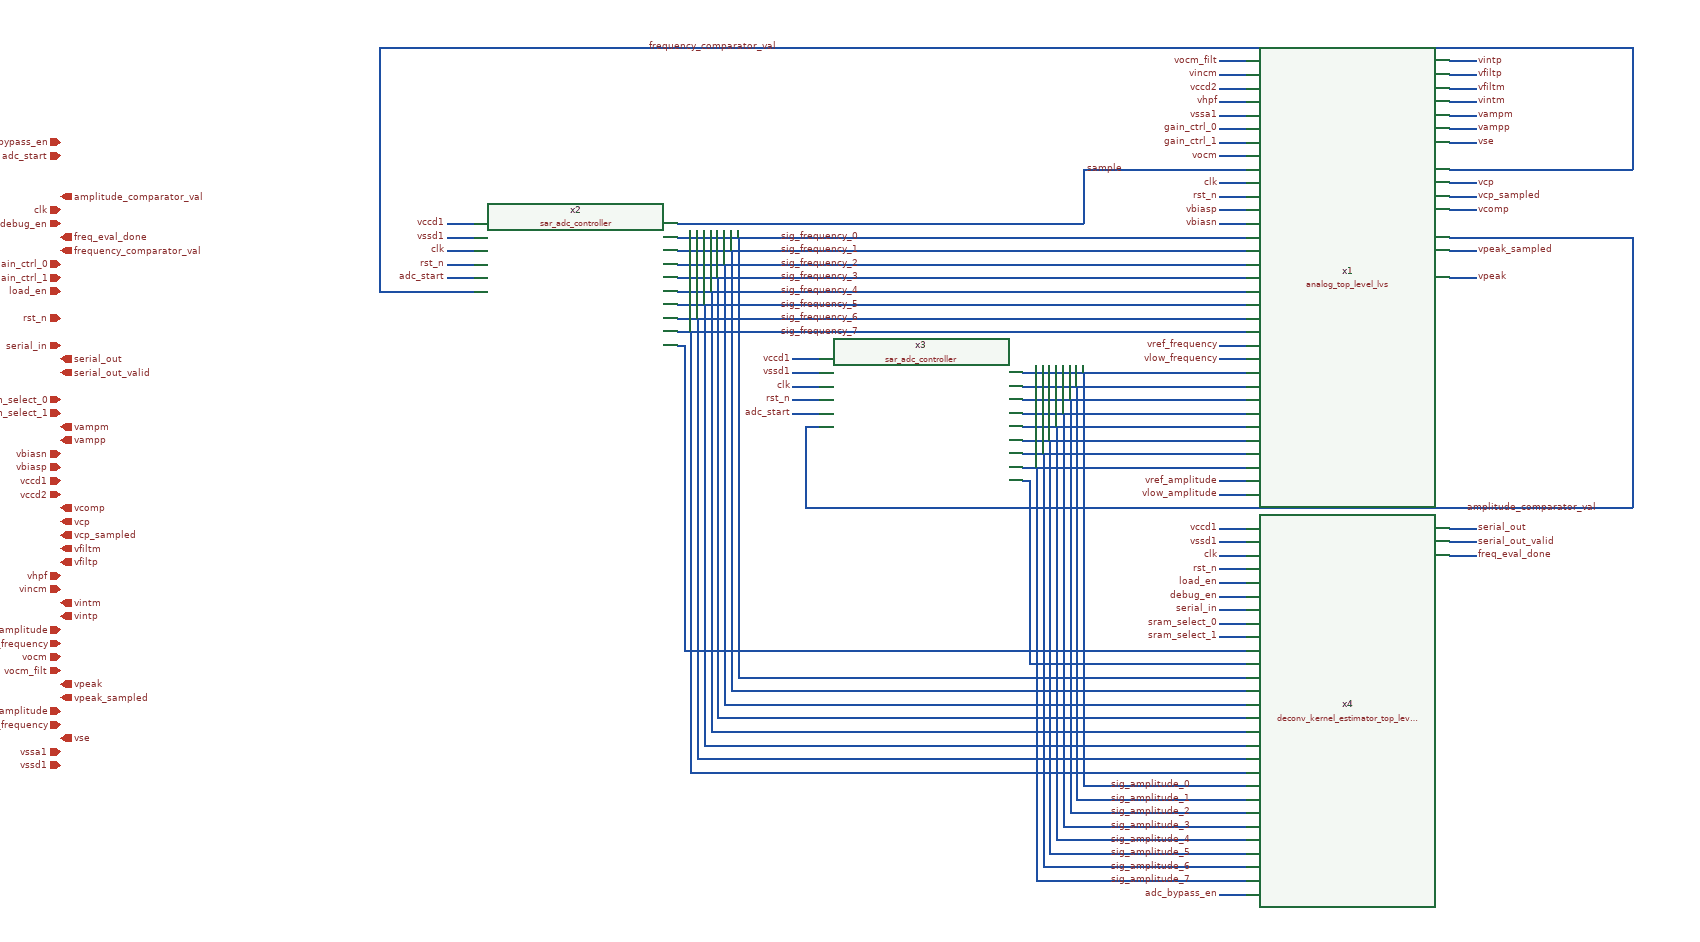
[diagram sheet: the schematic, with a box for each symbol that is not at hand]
v {xschem version=2.9.9 file_version=1.2 }
G {}
K {}
V {}
S {}
E {}
N 1400 -700 1440 -700 { lab=vlow_amplitude}
N 1400 -720 1440 -720 { lab=vref_amplitude}
N 1400 -900 1440 -900 { lab=vlow_frequency}
N 1400 -920 1440 -920 { lab=vref_frequency}
N 1400 -1100 1440 -1100 { lab=vbiasn}
N 1400 -1120 1440 -1120 { lab=vbiasp}
N 1400 -1200 1440 -1200 { lab=vocm}
N 1400 -1280 1440 -1280 { lab=vhpf}
N 1400 -1320 1440 -1320 { lab=vincm}
N 1400 -1340 1440 -1340 { lab=vocm_filt}
N 1740 -1340 1780 -1340 { lab=vfiltp}
N 1740 -1320 1780 -1320 { lab=vfiltp}
N 1740 -1300 1780 -1300 { lab=vfiltm}
N 1740 -1280 1780 -1280 { lab=vintm}
N 1740 -1260 1780 -1260 { lab=vampm}
N 1740 -1240 1780 -1240 { lab=vampp}
N 1740 -1220 1780 -1220 { lab=vse}
N 1740 -1160 1780 -1160 { lab=vcp}
N 1740 -1140 1780 -1140 { lab=vcp_sampled}
N 1740 -1020 1780 -1020 { lab=vpeak}
N 1740 -1060 1780 -1060 { lab=vpeak_sampled}
N 1740 -1120 1780 -1120 { lab=vcomp}
N 1400 -1240 1440 -1240 { lab=gain_ctrl_0}
N 1400 -1220 1440 -1220 { lab=gain_ctrl_1}
N 1400 -1180 1440 -1180 { lab=sample}
N 1400 -1160 1440 -1160 { lab=clk}
N 1400 -1300 1440 -1300 { lab=vccd2}
N 1400 -1260 1440 -1260 { lab=vssa1}
N 1200 -1180 1400 -1180 { lab=sample}
N 600 -1080 1440 -1080 { lab=sig_frequency_0}
N 1130 -740 1130 -510 { lab=sig_amplitude_7}
N 1140 -760 1140 -520 { lab=sig_amplitude_6}
N 1150 -780 1150 -530 { lab=sig_amplitude_5}
N 1160 -800 1160 -540 { lab=sig_amplitude_4}
N 1170 -820 1170 -550 { lab=sig_amplitude_3}
N 1180 -840 1180 -560 { lab=sig_amplitude_2}
N 1190 -860 1190 -570 { lab=sig_amplitude_1}
N 1200 -880 1200 -580 { lab=sig_amplitude_0}
N 1200 -270 1440 -270 { lab=sig_amplitude_0}
N 1190 -250 1440 -250 { lab=sig_amplitude_1}
N 1180 -230 1440 -230 { lab=sig_amplitude_2}
N 1170 -210 1440 -210 { lab=sig_amplitude_3}
N 1160 -190 1440 -190 { lab=sig_amplitude_4}
N 1150 -170 1440 -170 { lab=sig_amplitude_5}
N 1140 -150 1440 -150 { lab=sig_amplitude_6}
N 1130 -130 1440 -130 { lab=sig_amplitude_7}
N 1110 -880 1440 -880 { lab=sig_amplitude_0}
N 1110 -860 1440 -860 { lab=sig_amplitude_1}
N 1110 -840 1440 -840 { lab=sig_amplitude_2}
N 1110 -820 1440 -820 { lab=sig_amplitude_3}
N 1110 -800 1440 -800 { lab=sig_amplitude_4}
N 1110 -780 1440 -780 { lab=sig_amplitude_5}
N 1110 -760 1440 -760 { lab=sig_amplitude_6}
N 1110 -740 1440 -740 { lab=sig_amplitude_7}
N 1200 -580 1200 -270 { lab=sig_amplitude_0}
N 1190 -570 1190 -250 { lab=sig_amplitude_1}
N 1180 -560 1180 -230 { lab=sig_amplitude_2}
N 1170 -550 1170 -210 { lab=sig_amplitude_3}
N 1160 -540 1160 -190 { lab=sig_amplitude_4}
N 1150 -530 1150 -170 { lab=sig_amplitude_5}
N 1140 -520 1140 -150 { lab=sig_amplitude_6}
N 1130 -510 1130 -130 { lab=sig_amplitude_7}
N 620 -940 620 -710 { lab=sig_frequency_7}
N 630 -960 630 -720 { lab=sig_frequency_6}
N 640 -980 640 -730 { lab=sig_frequency_5}
N 650 -1000 650 -740 { lab=sig_frequency_4}
N 660 -1020 660 -750 { lab=sig_frequency_3}
N 670 -1040 670 -760 { lab=sig_frequency_2}
N 680 -1060 680 -770 { lab=sig_frequency_1}
N 690 -1080 690 -780 { lab=sig_frequency_0}
N 620 -290 1440 -290 { lab=sig_frequency_7}
N 620 -710 620 -290 { lab=sig_frequency_7}
N 630 -720 630 -310 { lab=sig_frequency_6}
N 630 -310 1440 -310 { lab=sig_frequency_6}
N 640 -330 1440 -330 { lab=sig_frequency_5}
N 640 -730 640 -330 { lab=sig_frequency_5}
N 650 -740 650 -350 { lab=sig_frequency_4}
N 650 -350 1440 -350 { lab=sig_frequency_4}
N 660 -370 1440 -370 { lab=sig_frequency_3}
N 660 -750 660 -370 { lab=sig_frequency_3}
N 670 -760 670 -390 { lab=sig_frequency_2}
N 670 -390 1440 -390 { lab=sig_frequency_2}
N 680 -410 1440 -410 { lab=sig_frequency_1}
N 680 -770 680 -410 { lab=sig_frequency_1}
N 690 -780 690 -430 { lab=sig_frequency_0}
N 690 -430 1440 -430 { lab=sig_frequency_0}
N 600 -1060 1440 -1060 { lab=sig_frequency_1}
N 600 -1040 1440 -1040 { lab=sig_frequency_2}
N 600 -1020 1440 -1020 { lab=sig_frequency_3}
N 600 -1000 1440 -1000 { lab=sig_frequency_4}
N 600 -980 1440 -980 { lab=sig_frequency_5}
N 600 -960 1440 -960 { lab=sig_frequency_6}
N 600 -940 1440 -940 { lab=sig_frequency_7}
N 600 -1100 1200 -1100 { lab=sample}
N 770 -900 810 -900 { lab=vccd1}
N 1400 -650 1440 -650 { lab=vccd1}
N 260 -1100 300 -1100 { lab=vccd1}
N 260 -1080 300 -1080 { lab=vssd1}
N 770 -880 810 -880 { lab=vssd1}
N 1400 -630 1440 -630 { lab=vssd1}
N 1110 -720 1120 -720 { lab=#net1}
N 1120 -720 1120 -450 { lab=#net1}
N 1120 -450 1440 -450 { lab=#net1}
N 600 -920 610 -920 { lab=#net2}
N 610 -470 1440 -470 { lab=#net2}
N 610 -920 610 -470 { lab=#net2}
N 1400 -510 1440 -510 { lab=sram_select_0}
N 1400 -490 1440 -490 { lab=sram_select_1}
N 1400 -610 1440 -610 { lab=clk}
N 1400 -590 1440 -590 { lab=rst_n}
N 260 -1060 300 -1060 { lab=clk}
N 260 -1040 300 -1040 { lab=rst_n}
N 770 -860 810 -860 { lab=clk}
N 770 -840 810 -840 { lab=rst_n}
N 260 -1020 300 -1020 { lab=adc_start}
N 770 -820 810 -820 { lab=adc_start}
N 160 -1360 2010 -1360 { lab=frequency_comparator_val}
N 160 -1360 160 -1000 { lab=frequency_comparator_val}
N 160 -1000 300 -1000 { lab=frequency_comparator_val}
N 2010 -1060 2010 -680 { lab=amplitude_comparator_val}
N 790 -680 2010 -680 { lab=amplitude_comparator_val}
N 790 -800 790 -680 { lab=amplitude_comparator_val}
N 790 -800 810 -800 { lab=amplitude_comparator_val}
N 1400 -570 1440 -570 { lab=load_en}
N 1400 -550 1440 -550 { lab=debug_en}
N 1400 -530 1440 -530 { lab=serial_in}
N 1740 -650 1780 -650 { lab=serial_out}
N 1740 -630 1780 -630 { lab=serial_out_valid}
N 1740 -610 1780 -610 { lab=freq_eval_done}
N 1400 -110 1440 -110 { lab=adc_bypass_en}
N 1200 -1180 1200 -1160 { lab=sample}
N 1400 -1140 1440 -1140 { lab=rst_n}
N 1740 -1180 2010 -1180 { lab=frequency_comparator_val}
N 2010 -1360 2010 -1180 { lab=frequency_comparator_val}
N 1740 -1080 2010 -1080 { lab=amplitude_comparator_val}
N 2010 -1080 2010 -1060 { lab=amplitude_comparator_val}
N 1200 -1160 1200 -1100 { lab=sample}
C {/home/users/nhpoole/ee272b/ee272b_mixed_signal_mmwave_accelerator/designs/analog_top_level_lvs.sym} 1590 -1020 0 0 {name=x1}
C {devices/lab_pin.sym} 1400 -700 0 0 {name=l13 sig_type=std_logic lab=vlow_amplitude}
C {devices/lab_pin.sym} 1400 -720 0 0 {name=l14 sig_type=std_logic lab=vref_amplitude}
C {devices/lab_pin.sym} 1400 -900 0 0 {name=l15 sig_type=std_logic lab=vlow_frequency}
C {devices/lab_pin.sym} 1400 -920 0 0 {name=l16 sig_type=std_logic lab=vref_frequency}
C {devices/lab_pin.sym} 1400 -1100 0 0 {name=l17 sig_type=std_logic lab=vbiasn}
C {devices/lab_pin.sym} 1400 -1120 0 0 {name=l18 sig_type=std_logic lab=vbiasp}
C {devices/lab_pin.sym} 1400 -1200 0 0 {name=l19 sig_type=std_logic lab=vocm}
C {devices/lab_pin.sym} 1400 -1280 0 0 {name=l20 sig_type=std_logic lab=vhpf}
C {devices/lab_pin.sym} 1400 -1320 0 0 {name=l21 sig_type=std_logic lab=vincm}
C {devices/lab_pin.sym} 1400 -1340 0 0 {name=l22 sig_type=std_logic lab=vocm_filt}
C {devices/lab_pin.sym} 1780 -1340 0 1 {name=l23 sig_type=std_logic lab=vintp}
C {devices/lab_pin.sym} 1780 -1320 0 1 {name=l24 sig_type=std_logic lab=vfiltp}
C {devices/lab_pin.sym} 1780 -1300 0 1 {name=l25 sig_type=std_logic lab=vfiltm}
C {devices/lab_pin.sym} 1780 -1280 0 1 {name=l26 sig_type=std_logic lab=vintm}
C {devices/lab_pin.sym} 1780 -1260 0 1 {name=l27 sig_type=std_logic lab=vampm}
C {devices/lab_pin.sym} 1780 -1240 0 1 {name=l28 sig_type=std_logic lab=vampp}
C {devices/lab_pin.sym} 1780 -1220 0 1 {name=l31 sig_type=std_logic lab=vse}
C {devices/lab_pin.sym} 1780 -1160 0 1 {name=l32 sig_type=std_logic lab=vcp}
C {devices/lab_pin.sym} 1780 -1140 0 1 {name=l33 sig_type=std_logic lab=vcp_sampled}
C {devices/lab_pin.sym} 1780 -1020 0 1 {name=l34 sig_type=std_logic lab=vpeak}
C {devices/lab_pin.sym} 1780 -1060 0 1 {name=l35 sig_type=std_logic lab=vpeak_sampled}
C {devices/lab_pin.sym} 1780 -1120 0 1 {name=l36 sig_type=std_logic lab=vcomp}
C {devices/lab_pin.sym} 1400 -1240 0 0 {name=l40 sig_type=std_logic lab=gain_ctrl_0}
C {devices/lab_pin.sym} 1400 -1220 0 0 {name=l41 sig_type=std_logic lab=gain_ctrl_1}
C {devices/lab_pin.sym} 1400 -1160 0 0 {name=l43 sig_type=std_logic lab=clk}
C {devices/lab_pin.sym} 1400 -1300 0 0 {name=l7 sig_type=std_logic lab=vccd2}
C {devices/lab_pin.sym} 1400 -1260 0 0 {name=l8 sig_type=std_logic lab=vssa1}
C {/home/users/nhpoole/ee272b/ee272b_mixed_signal_mmwave_accelerator/designs/sar_adc_controller.sym} 450 -1010 0 0 {name=x2}
C {/home/users/nhpoole/ee272b/ee272b_mixed_signal_mmwave_accelerator/designs/sar_adc_controller.sym} 960 -810 0 0 {name=x3}
C {/home/users/nhpoole/ee272b/ee272b_mixed_signal_mmwave_accelerator/designs/deconv_kernel_estimator_top_level.sym} 1590 -380 0 0 {name=x4}
C {devices/lab_wire.sym} 870 -1080 0 0 {name=l1 sig_type=std_logic lab=sig_frequency_0}
C {devices/lab_wire.sym} 870 -1060 0 0 {name=l2 sig_type=std_logic lab=sig_frequency_1}
C {devices/lab_wire.sym} 870 -1040 0 0 {name=l3 sig_type=std_logic lab=sig_frequency_2}
C {devices/lab_wire.sym} 870 -1020 0 0 {name=l4 sig_type=std_logic lab=sig_frequency_3}
C {devices/lab_wire.sym} 870 -1000 0 0 {name=l5 sig_type=std_logic lab=sig_frequency_4}
C {devices/lab_wire.sym} 870 -980 0 0 {name=l6 sig_type=std_logic lab=sig_frequency_5}
C {devices/lab_wire.sym} 870 -960 0 0 {name=l9 sig_type=std_logic lab=sig_frequency_6}
C {devices/lab_wire.sym} 870 -940 0 0 {name=l10 sig_type=std_logic lab=sig_frequency_7}
C {devices/lab_wire.sym} 1260 -1180 0 0 {name=l42 sig_type=std_logic lab=sample}
C {devices/lab_wire.sym} 1360 -270 0 0 {name=l11 sig_type=std_logic lab=sig_amplitude_0}
C {devices/lab_wire.sym} 1360 -250 0 0 {name=l12 sig_type=std_logic lab=sig_amplitude_1}
C {devices/lab_wire.sym} 1360 -230 0 0 {name=l44 sig_type=std_logic lab=sig_amplitude_2}
C {devices/lab_wire.sym} 1360 -210 0 0 {name=l45 sig_type=std_logic lab=sig_amplitude_3}
C {devices/lab_wire.sym} 1360 -190 0 0 {name=l46 sig_type=std_logic lab=sig_amplitude_4}
C {devices/lab_wire.sym} 1360 -170 0 0 {name=l47 sig_type=std_logic lab=sig_amplitude_5}
C {devices/lab_wire.sym} 1360 -150 0 0 {name=l48 sig_type=std_logic lab=sig_amplitude_6}
C {devices/lab_wire.sym} 1360 -130 0 0 {name=l49 sig_type=std_logic lab=sig_amplitude_7}
C {devices/noconn.sym} 1110 -900 0 1 {name=l50}
C {devices/lab_pin.sym} 770 -900 0 0 {name=l51 sig_type=std_logic lab=vccd1}
C {devices/lab_pin.sym} 1400 -650 0 0 {name=l52 sig_type=std_logic lab=vccd1}
C {devices/lab_pin.sym} 260 -1100 0 0 {name=l53 sig_type=std_logic lab=vccd1}
C {devices/lab_pin.sym} 260 -1080 0 0 {name=l54 sig_type=std_logic lab=vssd1}
C {devices/lab_pin.sym} 770 -880 0 0 {name=l55 sig_type=std_logic lab=vssd1}
C {devices/lab_pin.sym} 1400 -630 0 0 {name=l56 sig_type=std_logic lab=vssd1}
C {devices/lab_pin.sym} 1400 -510 0 0 {name=l57 sig_type=std_logic lab=sram_select_0}
C {devices/lab_pin.sym} 1400 -490 0 0 {name=l58 sig_type=std_logic lab=sram_select_1}
C {devices/lab_pin.sym} 1400 -610 0 0 {name=l59 sig_type=std_logic lab=clk}
C {devices/lab_pin.sym} 1400 -590 0 0 {name=l60 sig_type=std_logic lab=rst_n}
C {devices/lab_pin.sym} 260 -1060 0 0 {name=l61 sig_type=std_logic lab=clk}
C {devices/lab_pin.sym} 260 -1040 0 0 {name=l62 sig_type=std_logic lab=rst_n}
C {devices/lab_pin.sym} 770 -860 0 0 {name=l63 sig_type=std_logic lab=clk}
C {devices/lab_pin.sym} 770 -840 0 0 {name=l64 sig_type=std_logic lab=rst_n}
C {devices/lab_pin.sym} 260 -1020 0 0 {name=l65 sig_type=std_logic lab=adc_start}
C {devices/lab_pin.sym} 770 -820 0 0 {name=l66 sig_type=std_logic lab=adc_start}
C {devices/lab_wire.sym} 750 -1360 0 0 {name=l37 sig_type=std_logic lab=frequency_comparator_val}
C {devices/lab_wire.sym} 1960 -680 0 0 {name=l38 sig_type=std_logic lab=amplitude_comparator_val}
C {devices/lab_pin.sym} 1400 -570 0 0 {name=l67 sig_type=std_logic lab=load_en}
C {devices/lab_pin.sym} 1400 -550 0 0 {name=l68 sig_type=std_logic lab=debug_en}
C {devices/lab_pin.sym} 1400 -530 0 0 {name=l69 sig_type=std_logic lab=serial_in}
C {devices/lab_pin.sym} 1780 -650 0 1 {name=l70 sig_type=std_logic lab=serial_out}
C {devices/lab_pin.sym} 1780 -630 0 1 {name=l71 sig_type=std_logic lab=serial_out_valid}
C {devices/lab_pin.sym} 1780 -610 0 1 {name=l72 sig_type=std_logic lab=freq_eval_done}
C {devices/lab_pin.sym} 1400 -110 0 0 {name=l73 sig_type=std_logic lab=adc_bypass_en}
C {devices/ipin.sym} -310 -300 0 0 { name=p1 lab=vssd1 }
C {devices/ipin.sym} -310 -320 0 0 { name=p2 lab=vssa1 }
C {devices/opin.sym} -310 -340 0 0 { name=p3 lab=vse }
C {devices/ipin.sym} -310 -360 0 0 { name=p4 lab=vref_frequency }
C {devices/ipin.sym} -310 -380 0 0 { name=p5 lab=vref_amplitude }
C {devices/opin.sym} -310 -400 0 0 { name=p6 lab=vpeak_sampled }
C {devices/opin.sym} -310 -420 0 0 { name=p7 lab=vpeak }
C {devices/ipin.sym} -310 -440 0 0 { name=p8 lab=vocm_filt }
C {devices/ipin.sym} -310 -460 0 0 { name=p9 lab=vocm }
C {devices/ipin.sym} -310 -480 0 0 { name=p10 lab=vlow_frequency }
C {devices/ipin.sym} -310 -500 0 0 { name=p11 lab=vlow_amplitude }
C {devices/opin.sym} -310 -520 0 0 { name=p12 lab=vintp }
C {devices/opin.sym} -310 -540 0 0 { name=p13 lab=vintm }
C {devices/ipin.sym} -310 -560 0 0 { name=p14 lab=vincm }
C {devices/ipin.sym} -310 -580 0 0 { name=p15 lab=vhpf }
C {devices/opin.sym} -310 -600 0 0 { name=p16 lab=vfiltp }
C {devices/opin.sym} -310 -620 0 0 { name=p17 lab=vfiltm }
C {devices/opin.sym} -310 -640 0 0 { name=p18 lab=vcp_sampled }
C {devices/opin.sym} -310 -660 0 0 { name=p19 lab=vcp }
C {devices/opin.sym} -310 -680 0 0 { name=p20 lab=vcomp }
C {devices/ipin.sym} -310 -700 0 0 { name=p21 lab=vccd2 }
C {devices/ipin.sym} -310 -720 0 0 { name=p22 lab=vccd1 }
C {devices/ipin.sym} -310 -740 0 0 { name=p23 lab=vbiasp }
C {devices/ipin.sym} -310 -760 0 0 { name=p24 lab=vbiasn }
C {devices/opin.sym} -310 -780 0 0 { name=p25 lab=vampp }
C {devices/opin.sym} -310 -800 0 0 { name=p26 lab=vampm }
C {devices/ipin.sym} -310 -820 0 0 { name=p27 lab=sram_select_1}
C {devices/opin.sym} -310 -880 0 0 { name=p30 lab=serial_out_valid }
C {devices/opin.sym} -310 -900 0 0 { name=p31 lab=serial_out }
C {devices/ipin.sym} -310 -920 0 0 { name=p32 lab=serial_in }
C {devices/ipin.sym} -310 -960 0 0 { name=p34 lab=rst_n }
C {devices/ipin.sym} -310 -1000 0 0 { name=p36 lab=load_en }
C {devices/ipin.sym} -310 -1020 0 0 { name=p37 lab=gain_ctrl_1 }
C {devices/ipin.sym} -310 -1040 0 0 { name=p38 lab=gain_ctrl_0 }
C {devices/opin.sym} -310 -1060 0 0 { name=p39 lab=frequency_comparator_val }
C {devices/opin.sym} -310 -1080 0 0 { name=p40 lab=freq_eval_done }
C {devices/ipin.sym} -310 -1100 0 0 { name=p41 lab=debug_en }
C {devices/ipin.sym} -310 -1120 0 0 { name=p42 lab=clk }
C {devices/opin.sym} -310 -1140 0 0 { name=p43 lab=amplitude_comparator_val }
C {devices/ipin.sym} -310 -1200 0 0 { name=p46 lab=adc_start }
C {devices/ipin.sym} -310 -1220 0 0 { name=p47 lab=adc_bypass_en }
C {devices/noconn.sym} 1740 -1200 0 1 {name=l29}
C {devices/noconn.sym} 1740 -1100 0 1 {name=l30}
C {devices/ipin.sym} -310 -840 0 0 { name=p28 lab=sram_select_0}
C {devices/lab_pin.sym} 1400 -1140 0 0 {name=l74 sig_type=std_logic lab=rst_n}
C {devices/noconn.sym} 1740 -1040 0 1 {name=l39}
